VERSION 5.7 ;
  NOWIREEXTENSIONATPIN ON ;
  DIVIDERCHAR "/" ;
  BUSBITCHARS "[]" ;
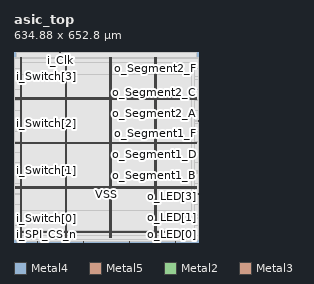
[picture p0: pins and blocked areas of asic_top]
MACRO asic_top
  CLASS BLOCK ;
  FOREIGN asic_top ;
  ORIGIN 0.000 0.000 ;
  SIZE 634.880 BY 652.800 ;
  PIN VDD
    DIRECTION INOUT ;
    USE POWER ;
    PORT
      LAYER Metal4 ;
        RECT 22.240 15.380 23.840 635.340 ;
    END
    PORT
      LAYER Metal4 ;
        RECT 175.840 15.380 177.440 635.340 ;
    END
    PORT
      LAYER Metal4 ;
        RECT 329.440 15.380 331.040 635.340 ;
    END
    PORT
      LAYER Metal4 ;
        RECT 483.040 15.380 484.640 635.340 ;
    END
    PORT
      LAYER Metal5 ;
        RECT 6.720 31.530 627.760 33.130 ;
    END
    PORT
      LAYER Metal5 ;
        RECT 6.720 184.710 627.760 186.310 ;
    END
    PORT
      LAYER Metal5 ;
        RECT 6.720 337.890 627.760 339.490 ;
    END
    PORT
      LAYER Metal5 ;
        RECT 6.720 491.070 627.760 492.670 ;
    END
  END VDD
  PIN VSS
    DIRECTION INOUT ;
    USE GROUND ;
    PORT
      LAYER Metal4 ;
        RECT 25.540 15.380 27.140 635.340 ;
    END
    PORT
      LAYER Metal4 ;
        RECT 179.140 15.380 180.740 635.340 ;
    END
    PORT
      LAYER Metal4 ;
        RECT 332.740 15.380 334.340 635.340 ;
    END
    PORT
      LAYER Metal4 ;
        RECT 486.340 15.380 487.940 635.340 ;
    END
    PORT
      LAYER Metal5 ;
        RECT 6.720 34.830 627.760 36.430 ;
    END
    PORT
      LAYER Metal5 ;
        RECT 6.720 188.010 627.760 189.610 ;
    END
    PORT
      LAYER Metal5 ;
        RECT 6.720 341.190 627.760 342.790 ;
    END
    PORT
      LAYER Metal5 ;
        RECT 6.720 494.370 627.760 495.970 ;
    END
  END VSS
  PIN i_Clk
    DIRECTION INPUT ;
    USE SIGNAL ;
    ANTENNAGATEAREA 4.738000 ;
    PORT
      LAYER Metal2 ;
        RECT 157.920 652.240 158.480 652.800 ;
    END
  END i_Clk
  PIN i_SPI_CS_n
    DIRECTION INPUT ;
    USE SIGNAL ;
    ANTENNAGATEAREA 0.396000 ;
    PORT
      LAYER Metal2 ;
        RECT 79.520 0.000 80.080 0.560 ;
    END
  END i_SPI_CS_n
  PIN i_SPI_MOSI
    DIRECTION INPUT ;
    USE SIGNAL ;
    ANTENNAGATEAREA 0.396000 ;
    PORT
      LAYER Metal2 ;
        RECT 237.440 0.000 238.000 0.560 ;
    END
  END i_SPI_MOSI
  PIN i_SPI_SCLK
    DIRECTION INPUT ;
    USE SIGNAL ;
    ANTENNAGATEAREA 0.396000 ;
    PORT
      LAYER Metal2 ;
        RECT 395.360 0.000 395.920 0.560 ;
    END
  END i_SPI_SCLK
  PIN i_Switch[0]
    DIRECTION INPUT ;
    USE SIGNAL ;
    ANTENNAGATEAREA 0.396000 ;
    PORT
      LAYER Metal3 ;
        RECT 0.000 81.760 0.560 82.320 ;
    END
  END i_Switch[0]
  PIN i_Switch[1]
    DIRECTION INPUT ;
    USE SIGNAL ;
    ANTENNAGATEAREA 0.396000 ;
    PORT
      LAYER Metal3 ;
        RECT 0.000 244.160 0.560 244.720 ;
    END
  END i_Switch[1]
  PIN i_Switch[2]
    DIRECTION INPUT ;
    USE SIGNAL ;
    ANTENNAGATEAREA 0.396000 ;
    PORT
      LAYER Metal3 ;
        RECT 0.000 406.560 0.560 407.120 ;
    END
  END i_Switch[2]
  PIN i_Switch[3]
    DIRECTION INPUT ;
    USE SIGNAL ;
    ANTENNAGATEAREA 0.396000 ;
    PORT
      LAYER Metal3 ;
        RECT 0.000 568.960 0.560 569.520 ;
    END
  END i_Switch[3]
  PIN o_LED[0]
    DIRECTION OUTPUT ;
    USE SIGNAL ;
    ANTENNADIFFAREA 0.897600 ;
    PORT
      LAYER Metal3 ;
        RECT 634.320 21.280 634.880 21.840 ;
    END
  END o_LED[0]
  PIN o_LED[1]
    DIRECTION OUTPUT ;
    USE SIGNAL ;
    ANTENNADIFFAREA 0.897600 ;
    PORT
      LAYER Metal3 ;
        RECT 634.320 57.120 634.880 57.680 ;
    END
  END o_LED[1]
  PIN o_LED[2]
    DIRECTION OUTPUT ;
    USE SIGNAL ;
    ANTENNADIFFAREA 0.897600 ;
    PORT
      LAYER Metal3 ;
        RECT 634.320 92.960 634.880 93.520 ;
    END
  END o_LED[2]
  PIN o_LED[3]
    DIRECTION OUTPUT ;
    USE SIGNAL ;
    ANTENNADIFFAREA 0.897600 ;
    PORT
      LAYER Metal3 ;
        RECT 634.320 128.800 634.880 129.360 ;
    END
  END o_LED[3]
  PIN o_SPI_MISO
    DIRECTION OUTPUT ;
    USE SIGNAL ;
    ANTENNADIFFAREA 0.897600 ;
    PORT
      LAYER Metal2 ;
        RECT 553.280 0.000 553.840 0.560 ;
    END
  END o_SPI_MISO
  PIN o_Segment1_A
    DIRECTION OUTPUT ;
    USE SIGNAL ;
    ANTENNADIFFAREA 0.897600 ;
    PORT
      LAYER Metal3 ;
        RECT 634.320 164.640 634.880 165.200 ;
    END
  END o_Segment1_A
  PIN o_Segment1_B
    DIRECTION OUTPUT ;
    USE SIGNAL ;
    ANTENNADIFFAREA 0.897600 ;
    PORT
      LAYER Metal3 ;
        RECT 634.320 200.480 634.880 201.040 ;
    END
  END o_Segment1_B
  PIN o_Segment1_C
    DIRECTION OUTPUT ;
    USE SIGNAL ;
    ANTENNADIFFAREA 0.897600 ;
    PORT
      LAYER Metal3 ;
        RECT 634.320 236.320 634.880 236.880 ;
    END
  END o_Segment1_C
  PIN o_Segment1_D
    DIRECTION OUTPUT ;
    USE SIGNAL ;
    ANTENNADIFFAREA 0.897600 ;
    PORT
      LAYER Metal3 ;
        RECT 634.320 272.160 634.880 272.720 ;
    END
  END o_Segment1_D
  PIN o_Segment1_E
    DIRECTION OUTPUT ;
    USE SIGNAL ;
    ANTENNADIFFAREA 0.897600 ;
    PORT
      LAYER Metal3 ;
        RECT 634.320 308.000 634.880 308.560 ;
    END
  END o_Segment1_E
  PIN o_Segment1_F
    DIRECTION OUTPUT ;
    USE SIGNAL ;
    ANTENNADIFFAREA 0.897600 ;
    PORT
      LAYER Metal3 ;
        RECT 634.320 343.840 634.880 344.400 ;
    END
  END o_Segment1_F
  PIN o_Segment1_G
    DIRECTION OUTPUT ;
    USE SIGNAL ;
    ANTENNADIFFAREA 0.897600 ;
    PORT
      LAYER Metal3 ;
        RECT 634.320 379.680 634.880 380.240 ;
    END
  END o_Segment1_G
  PIN o_Segment2_A
    DIRECTION OUTPUT ;
    USE SIGNAL ;
    ANTENNADIFFAREA 0.897600 ;
    PORT
      LAYER Metal3 ;
        RECT 634.320 415.520 634.880 416.080 ;
    END
  END o_Segment2_A
  PIN o_Segment2_B
    DIRECTION OUTPUT ;
    USE SIGNAL ;
    ANTENNADIFFAREA 0.897600 ;
    PORT
      LAYER Metal3 ;
        RECT 634.320 451.360 634.880 451.920 ;
    END
  END o_Segment2_B
  PIN o_Segment2_C
    DIRECTION OUTPUT ;
    USE SIGNAL ;
    ANTENNADIFFAREA 0.897600 ;
    PORT
      LAYER Metal3 ;
        RECT 634.320 487.200 634.880 487.760 ;
    END
  END o_Segment2_C
  PIN o_Segment2_D
    DIRECTION OUTPUT ;
    USE SIGNAL ;
    ANTENNADIFFAREA 0.897600 ;
    PORT
      LAYER Metal3 ;
        RECT 634.320 523.040 634.880 523.600 ;
    END
  END o_Segment2_D
  PIN o_Segment2_E
    DIRECTION OUTPUT ;
    USE SIGNAL ;
    ANTENNADIFFAREA 0.897600 ;
    PORT
      LAYER Metal3 ;
        RECT 634.320 558.880 634.880 559.440 ;
    END
  END o_Segment2_E
  PIN o_Segment2_F
    DIRECTION OUTPUT ;
    USE SIGNAL ;
    ANTENNADIFFAREA 0.897600 ;
    PORT
      LAYER Metal3 ;
        RECT 634.320 594.720 634.880 595.280 ;
    END
  END o_Segment2_F
  PIN o_Segment2_G
    DIRECTION OUTPUT ;
    USE SIGNAL ;
    ANTENNADIFFAREA 0.897600 ;
    PORT
      LAYER Metal3 ;
        RECT 634.320 630.560 634.880 631.120 ;
    END
  END o_Segment2_G
  PIN rst_ni
    DIRECTION INPUT ;
    USE SIGNAL ;
    ANTENNAGATEAREA 0.396000 ;
    PORT
      LAYER Metal2 ;
        RECT 474.880 652.240 475.440 652.800 ;
    END
  END rst_ni
  OBS
      LAYER Nwell ;
        RECT 6.290 15.250 628.190 635.470 ;
      LAYER Metal1 ;
        RECT 6.720 15.380 627.760 635.340 ;
      LAYER Metal2 ;
        RECT 8.540 651.940 157.620 652.240 ;
        RECT 158.780 651.940 474.580 652.240 ;
        RECT 475.740 651.940 625.940 652.240 ;
        RECT 8.540 0.860 625.940 651.940 ;
        RECT 8.540 0.560 79.220 0.860 ;
        RECT 80.380 0.560 237.140 0.860 ;
        RECT 238.300 0.560 395.060 0.860 ;
        RECT 396.220 0.560 552.980 0.860 ;
        RECT 554.140 0.560 625.940 0.860 ;
      LAYER Metal3 ;
        RECT 0.560 631.420 634.320 635.180 ;
        RECT 0.560 630.260 634.020 631.420 ;
        RECT 0.560 595.580 634.320 630.260 ;
        RECT 0.560 594.420 634.020 595.580 ;
        RECT 0.560 569.820 634.320 594.420 ;
        RECT 0.860 568.660 634.320 569.820 ;
        RECT 0.560 559.740 634.320 568.660 ;
        RECT 0.560 558.580 634.020 559.740 ;
        RECT 0.560 523.900 634.320 558.580 ;
        RECT 0.560 522.740 634.020 523.900 ;
        RECT 0.560 488.060 634.320 522.740 ;
        RECT 0.560 486.900 634.020 488.060 ;
        RECT 0.560 452.220 634.320 486.900 ;
        RECT 0.560 451.060 634.020 452.220 ;
        RECT 0.560 416.380 634.320 451.060 ;
        RECT 0.560 415.220 634.020 416.380 ;
        RECT 0.560 407.420 634.320 415.220 ;
        RECT 0.860 406.260 634.320 407.420 ;
        RECT 0.560 380.540 634.320 406.260 ;
        RECT 0.560 379.380 634.020 380.540 ;
        RECT 0.560 344.700 634.320 379.380 ;
        RECT 0.560 343.540 634.020 344.700 ;
        RECT 0.560 308.860 634.320 343.540 ;
        RECT 0.560 307.700 634.020 308.860 ;
        RECT 0.560 273.020 634.320 307.700 ;
        RECT 0.560 271.860 634.020 273.020 ;
        RECT 0.560 245.020 634.320 271.860 ;
        RECT 0.860 243.860 634.320 245.020 ;
        RECT 0.560 237.180 634.320 243.860 ;
        RECT 0.560 236.020 634.020 237.180 ;
        RECT 0.560 201.340 634.320 236.020 ;
        RECT 0.560 200.180 634.020 201.340 ;
        RECT 0.560 165.500 634.320 200.180 ;
        RECT 0.560 164.340 634.020 165.500 ;
        RECT 0.560 129.660 634.320 164.340 ;
        RECT 0.560 128.500 634.020 129.660 ;
        RECT 0.560 93.820 634.320 128.500 ;
        RECT 0.560 92.660 634.020 93.820 ;
        RECT 0.560 82.620 634.320 92.660 ;
        RECT 0.860 81.460 634.320 82.620 ;
        RECT 0.560 57.980 634.320 81.460 ;
        RECT 0.560 56.820 634.020 57.980 ;
        RECT 0.560 22.140 634.320 56.820 ;
        RECT 0.560 20.980 634.020 22.140 ;
        RECT 0.560 8.540 634.320 20.980 ;
      LAYER Metal4 ;
        RECT 20.860 40.410 21.940 618.150 ;
        RECT 24.140 40.410 25.240 618.150 ;
        RECT 27.440 40.410 175.540 618.150 ;
        RECT 177.740 40.410 178.840 618.150 ;
        RECT 181.040 40.410 329.140 618.150 ;
        RECT 331.340 40.410 332.440 618.150 ;
        RECT 334.640 40.410 482.740 618.150 ;
        RECT 484.940 40.410 486.040 618.150 ;
        RECT 488.240 40.410 620.900 618.150 ;
      LAYER Metal5 ;
        RECT 20.780 496.570 609.780 573.970 ;
        RECT 20.780 493.270 609.780 493.770 ;
        RECT 20.780 343.390 609.780 490.470 ;
        RECT 20.780 340.090 609.780 340.590 ;
        RECT 20.780 190.210 609.780 337.290 ;
        RECT 20.780 186.910 609.780 187.410 ;
        RECT 20.780 107.330 609.780 184.110 ;
  END
END asic_top
END LIBRARY

